One B-rep face of a CAD part: STEP entity #7666.
In plain terms, the planar face has unit normal (0, -1, 0).
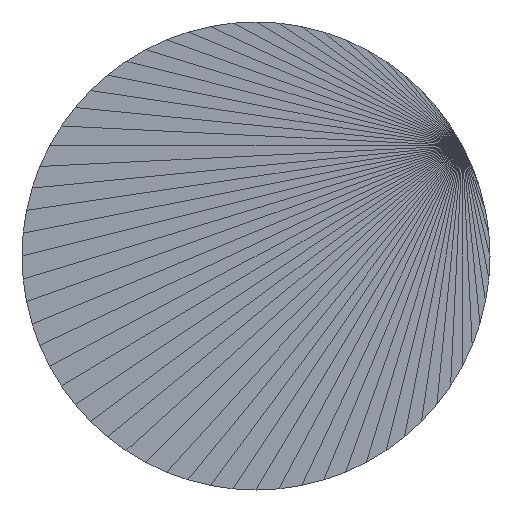
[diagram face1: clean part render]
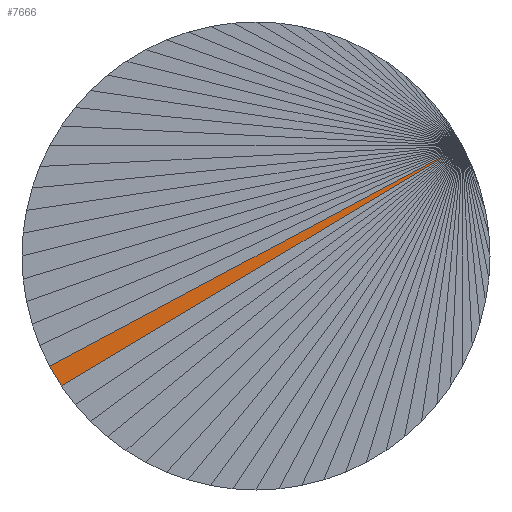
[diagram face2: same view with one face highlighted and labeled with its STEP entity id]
Its self-contained STEP definition (entity closure, numbers rounded to 3 decimals):
#1847 = VERTEX_POINT('',#1848);
#1848 = CARTESIAN_POINT('',(-172.611,-85.75,381.365));
#6189 = VERTEX_POINT('',#6190);
#6190 = CARTESIAN_POINT('',(-322.961,-85.75,291.249));
#6204 = PLANE('',#6205);
#6205 = AXIS2_PLACEMENT_3D('',#6206,#6207,#6208);
#6206 = CARTESIAN_POINT('',(-248.281,-85.75,333.457));
#6207 = DIRECTION('',(-0.,-1.,-0.));
#6208 = DIRECTION('',(0.,0.,-1.));
#6419 = PLANE('',#6420);
#6420 = AXIS2_PLACEMENT_3D('',#6421,#6422,#6423);
#6421 = CARTESIAN_POINT('',(-325.995,-79.595,
    296.31));
#6422 = DIRECTION('',(-0.858,-0.,-0.514));
#6423 = DIRECTION('',(0.514,0.,-0.858));
#6435 = VERTEX_POINT('',#6436);
#6436 = CARTESIAN_POINT('',(-327.389,-85.75,298.635));
#6475 = PLANE('',#6476);
#6476 = AXIS2_PLACEMENT_3D('',#6477,#6478,#6479);
#6477 = CARTESIAN_POINT('',(-252.796,-85.75,341.001));
#6478 = DIRECTION('',(-0.,-1.,-0.));
#6479 = DIRECTION('',(0.,0.,-1.));
#6540 = EDGE_CURVE('',#6189,#6435,#6541,.T.);
#6541 = SURFACE_CURVE('',#6542,(#6546,#6553),.PCURVE_S1.);
#6542 = LINE('',#6543,#6544);
#6543 = CARTESIAN_POINT('',(-322.961,-85.75,291.249));
#6544 = VECTOR('',#6545,1.);
#6545 = DIRECTION('',(-0.514,0.,0.858));
#6546 = PCURVE('',#6419,#6547);
#6547 = DEFINITIONAL_REPRESENTATION('',(#6548),#6552);
#6548 = LINE('',#6549,#6550);
#6549 = CARTESIAN_POINT('',(5.901,6.155));
#6550 = VECTOR('',#6551,1.);
#6551 = DIRECTION('',(-1.,0.));
#6552 = ( GEOMETRIC_REPRESENTATION_CONTEXT(2) 
PARAMETRIC_REPRESENTATION_CONTEXT() REPRESENTATION_CONTEXT('2D SPACE',''
  ) );
#6553 = PCURVE('',#6554,#6559);
#6554 = PLANE('',#6555);
#6555 = AXIS2_PLACEMENT_3D('',#6556,#6557,#6558);
#6556 = CARTESIAN_POINT('',(-250.722,-85.75,337.119));
#6557 = DIRECTION('',(-0.,-1.,-0.));
#6558 = DIRECTION('',(0.,0.,-1.));
#6559 = DEFINITIONAL_REPRESENTATION('',(#6560),#6563);
#6560 = B_SPLINE_CURVE_WITH_KNOTS('',1,(#6561,#6562),.UNSPECIFIED.,.F.,
  .F.,(2,2),(0.,8.611),.PIECEWISE_BEZIER_KNOTS.);
#6561 = CARTESIAN_POINT('',(45.87,-72.24));
#6562 = CARTESIAN_POINT('',(38.484,-76.667));
#6563 = ( GEOMETRIC_REPRESENTATION_CONTEXT(2) 
PARAMETRIC_REPRESENTATION_CONTEXT() REPRESENTATION_CONTEXT('2D SPACE',''
  ) );
#7329 = EDGE_CURVE('',#6435,#1847,#7330,.T.);
#7330 = SURFACE_CURVE('',#7331,(#7335,#7342),.PCURVE_S1.);
#7331 = LINE('',#7332,#7333);
#7332 = CARTESIAN_POINT('',(-327.389,-85.75,298.635));
#7333 = VECTOR('',#7334,1.);
#7334 = DIRECTION('',(0.882,0.,0.471));
#7335 = PCURVE('',#6475,#7336);
#7336 = DEFINITIONAL_REPRESENTATION('',(#7337),#7341);
#7337 = LINE('',#7338,#7339);
#7338 = CARTESIAN_POINT('',(42.366,-74.592));
#7339 = VECTOR('',#7340,1.);
#7340 = DIRECTION('',(-0.471,0.882));
#7341 = ( GEOMETRIC_REPRESENTATION_CONTEXT(2) 
PARAMETRIC_REPRESENTATION_CONTEXT() REPRESENTATION_CONTEXT('2D SPACE',''
  ) );
#7342 = PCURVE('',#6554,#7343);
#7343 = DEFINITIONAL_REPRESENTATION('',(#7344),#7347);
#7344 = B_SPLINE_CURVE_WITH_KNOTS('',1,(#7345,#7346),.UNSPECIFIED.,.F.,
  .F.,(2,2),(0.,175.5),.PIECEWISE_BEZIER_KNOTS.);
#7345 = CARTESIAN_POINT('',(38.484,-76.667));
#7346 = CARTESIAN_POINT('',(-44.246,78.11));
#7347 = ( GEOMETRIC_REPRESENTATION_CONTEXT(2) 
PARAMETRIC_REPRESENTATION_CONTEXT() REPRESENTATION_CONTEXT('2D SPACE',''
  ) );
#7666 = ADVANCED_FACE('',(#7667),#6554,.T.);
#7667 = FACE_BOUND('',#7668,.T.);
#7668 = EDGE_LOOP('',(#7669,#7670,#7671));
#7669 = ORIENTED_EDGE('',*,*,#7329,.F.);
#7670 = ORIENTED_EDGE('',*,*,#6540,.F.);
#7671 = ORIENTED_EDGE('',*,*,#7672,.T.);
#7672 = EDGE_CURVE('',#6189,#1847,#7673,.T.);
#7673 = SURFACE_CURVE('',#7674,(#7678,#7685),.PCURVE_S1.);
#7674 = LINE('',#7675,#7676);
#7675 = CARTESIAN_POINT('',(-322.961,-85.75,291.249));
#7676 = VECTOR('',#7677,1.);
#7677 = DIRECTION('',(0.858,0.,0.514));
#7678 = PCURVE('',#6554,#7679);
#7679 = DEFINITIONAL_REPRESENTATION('',(#7680),#7684);
#7680 = LINE('',#7681,#7682);
#7681 = CARTESIAN_POINT('',(45.87,-72.24));
#7682 = VECTOR('',#7683,1.);
#7683 = DIRECTION('',(-0.514,0.858));
#7684 = ( GEOMETRIC_REPRESENTATION_CONTEXT(2) 
PARAMETRIC_REPRESENTATION_CONTEXT() REPRESENTATION_CONTEXT('2D SPACE',''
  ) );
#7685 = PCURVE('',#6204,#7686);
#7686 = DEFINITIONAL_REPRESENTATION('',(#7687),#7690);
#7687 = B_SPLINE_CURVE_WITH_KNOTS('',1,(#7688,#7689),.UNSPECIFIED.,.F.,
  .F.,(2,2),(0.,175.289),.PIECEWISE_BEZIER_KNOTS.);
#7688 = CARTESIAN_POINT('',(42.208,-74.681));
#7689 = CARTESIAN_POINT('',(-47.908,75.67));
#7690 = ( GEOMETRIC_REPRESENTATION_CONTEXT(2) 
PARAMETRIC_REPRESENTATION_CONTEXT() REPRESENTATION_CONTEXT('2D SPACE',''
  ) );
